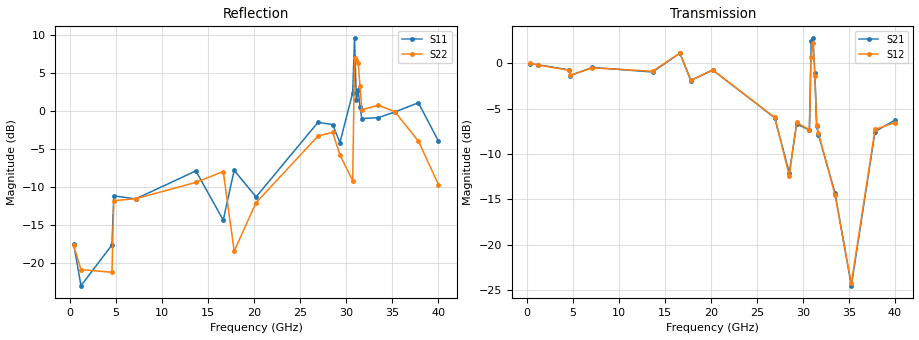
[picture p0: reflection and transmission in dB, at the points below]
! Network Analyzer HP8722ES.07.66: Jul 25, 2000 Serial No. US39175408
! 27 Oct 2004  10:35:24
! Frequency  S11  S21  S12  S22
# HZ  S  DB R  50
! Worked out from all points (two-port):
!   201 points, 400 MHz to 40 GHz, reference 50 ohm
!   highest |S21| = 2.74 dB at 31.09 GHz (marker M1); lowest = -24.5 dB at 35.25 GHz (marker M2)
!   |S21| within 3 dB of the highest: start of sweep to 2.79 GHz; 3.15 GHz to 4.36 GHz (1.211 GHz wide, 32.2 % of centre) (the widest 2 of 4)
!   lowest |S11| = -23.0 dB at 1.192 GHz (marker M3), VSWR 1.15, Z = 49.5 - j7.01 ohm
!   |S11| at or under -10 dB: start of sweep to 8.283 GHz; 16.24 GHz to 17.03 GHz (787.7 MHz wide, 4.74 % of centre); 18.15 GHz to 22.04 GHz (3.887 GHz wide, 19.3 % of centre)
!   |S22| runs from -21.8 to 6.9 dB; largest |S21 - S12| = 0.68
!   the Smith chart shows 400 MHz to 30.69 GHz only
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4e8  -17.54 -90.3  -0.07 4.8  -0.01 5.5  -17.75 -85.6
1.192e9  -23.04 -90.1  -0.16 -1.3  -0.20 -1.8  -20.93 -94.2
4.558e9  -17.67 -59.6  -0.73 -18.8  -0.77 -18.9  -21.27 -87.5
4.756e9  -11.22 -75.9  -1.36 -10.3  -1.31 -10.1  -11.85 -79.2
7.132e9  -11.62 -94.7  -0.46 -19.6  -0.51 -20.2  -11.60 -123.3
1.3666e10  -7.94 -87.1  -0.97 -31.1  -0.89 -31.7  -9.45 -149.1
1.6636e10  -14.41 -72.7  1.10 -49.0  1.13 -49.6  -8.02 133.9
1.7824e10  -7.87 -67.8  -1.91 -48.2  -1.90 -48.8  -18.49 87.7
2.02e10  -11.36 -9.9  -0.75 -58.3  -0.74 -58.6  -12.12 51.7
2.6932e10  -1.54 24.8  -6.02 -98.4  -5.98 -100.3  -3.34 -31.2
2.8516e10  -1.85 4.3  -12.10 -85.7  -12.43 -86.1  -2.87 -59.9
2.9308e10  -4.21 25.3  -6.70 -65.9  -6.54 -67.1  -5.84 -63.7
3.0694e10  2.36 5.0  -7.37 -112.7  -7.34 -112.5  -9.22 -65.6
3.0892e10  9.50 -9.4  2.47 84.7  0.72 54.0  6.92 -9.6
3.109e10  1.34 -32.1  2.74 -163.1  2.25 -163.9  6.64 150.0
3.1288e10  2.68 -25.3  -1.12 -87.6  -1.37 -88.6  6.30 -106.2
3.1486e10  0.47 -14.0  -6.92 -60.1  -6.87 -62.2  3.18 -68.8
3.1684e10  -1.05 -16.6  -7.92 -73.9  -7.70 -75.3  0.11 -70.2
3.3466e10  -0.93 -14.2  -14.27 -99.4  -14.51 -100.0  0.70 -70.8
3.5248e10  -0.20 -21.4  -24.54 -34.9  -24.28 -29.2  -0.13 -93.8
3.7822e10  1.03 -39.2  -7.54 -0.3  -7.30 -1.4  -4.01 -124.5
4e10  -4.01 -34.9  -6.27 -50.4  -6.55 -52.2  -9.73 -116.9
